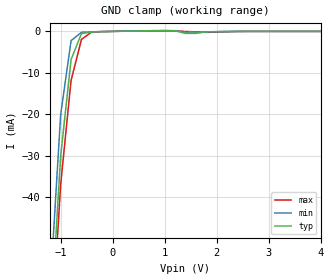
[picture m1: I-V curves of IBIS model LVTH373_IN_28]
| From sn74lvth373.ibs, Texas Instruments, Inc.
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|   Model LVTH373_IN_28
[Model]   LVTH373_IN_28
Model_type  Input
Polarity   Non-Inverting
Vinl = 0.8
Vinh = 2.0
| variable   typ   min   max
C_comp   3p   NA   NA
[Temperature Range]   40   -25   100
| Ambient temperature   25   -40   85
[Voltage range]   2.8   2.7   2.9
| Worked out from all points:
|   GND clamp passes 1 mA (typ) near -0.62 V on its own axis
[GND Clamp]
|   Voltage   I(typ)   I(min)   I(max)
-5V       -1.358A    -1.475A    -1.266A
-1.2V     -72.06mA   -61.52mA   -77.72mA
-1V       -29.98mA   -20.03mA   -36.89mA
-800mV    -6.803mA   -2.232mA   -11.84mA
-600mV    -520.1uA   -216.3uA   -1.92mA
-400mV    -101uA     -115.8uA   -121.8uA
-200mV    -48.7uA    -56.5uA    -43uA
1.2V      163.5uA    141.6uA    158.1uA
1.4V      -477.7uA   -297.5uA   -26.7uA
1.6V      -476.4uA   -217.6uA   -99.71uA
1.8V      -83.11uA   -130.5uA   -239.5uA
5V        198.3pA    92.82pA    3.595nA
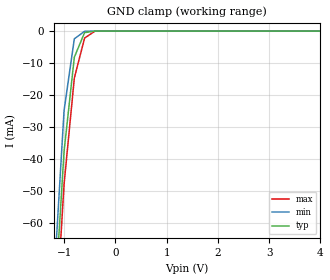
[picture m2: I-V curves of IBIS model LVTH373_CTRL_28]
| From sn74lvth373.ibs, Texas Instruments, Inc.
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|   Model LVTH373_CTRL_28
[Model]   LVTH373_CTRL_28
Model_type  Input
Polarity   Non-Inverting
Vinl = 0.8
Vinh = 2.0
| variable   typ   min   max
C_comp   3p   NA   NA
[Temperature Range]   40   -25   100
| Ambient temperature   25   -40   85
[Voltage range]   2.8   2.7   2.9
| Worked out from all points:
|   GND clamp passes 1 mA (typ) near -0.61 V on its own axis
[GND Clamp]
|   Voltage   I(typ)   I(min)   I(max)
-5V       -1.499A    -1.561A    -1.465A
-1.2V     -89.53mA   -78.73mA   -100.9mA
-1V       -37.49mA   -24.77mA   -47.75mA
-800mV    -8.144mA   -2.422mA   -14.66mA
-600mV    -479uA     -59.67uA   -2.181mA
-400mV    -1.318uA   -21.54nA   -41.73uA
5V        215.8pA    251.5pA    3.47nA
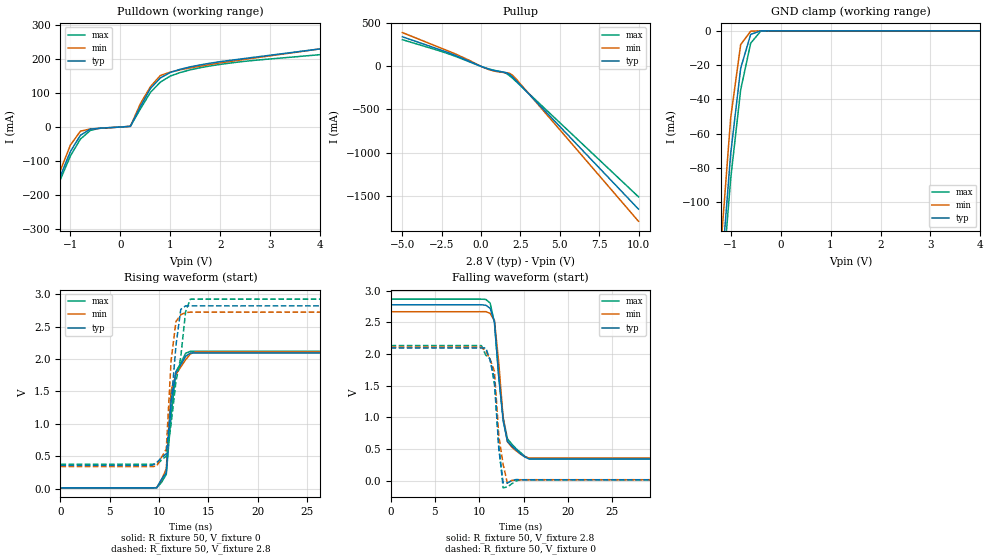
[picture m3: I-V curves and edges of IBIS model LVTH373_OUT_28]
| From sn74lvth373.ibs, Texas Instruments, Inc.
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|   Model LVTH373_OUT_28
[Model]   LVTH373_OUT_28
Model_type  3-state
Polarity   Inverting
Enable   Active-Low
Vmeas = 1.5v
Cref = 50pf
Rref = 500
Vref = 0V
| variable   typ   min   max
C_comp   7p   NA   NA
[Temperature Range]   40   -25   100
| Ambient temperature   25   -40   85
[Voltage range]   2.8   2.7   2.9
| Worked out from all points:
|   slope of the pulldown table from 0 to 0.42 V, typ, clamps not added: 6.46 ohm
|   slope of the pullup table from 0 to 0.42 V, typ, clamps not added: 15.3 ohm
|   GND clamp passes 1 mA (typ) near -0.50 V on its own axis
|   rising waveform, R_fixture 50, V_fixture 0: 20-80 % time 768ps typ, 785ps min, 787ps max; typ from 0.01 V to 2.09 V
|   falling waveform, R_fixture 50, V_fixture 2.8: 20-80 % time 1.03ns typ, 961ps min, 1.11ns max; typ from 2.78 V to 0.34 V
|   rising waveform, R_fixture 50, V_fixture 2.8: 20-80 % time 885ps typ, 636ps min, 1.36ns max; typ from 0.357 V to 2.82 V
|   falling waveform, R_fixture 50, V_fixture 0: 20-80 % time 672ps typ, 770ps min, 803ps max; typ from 2.1 V to 0.012 V
[Pulldown]
|   Voltage   I(typ)   I(min)   I(max)
-5V       -1.735A    -1.814A    -1.694A
-1.6V     -310.8mA   -304.6mA   -315.7mA
-1V       -71.87mA   -52.82mA   -84.79mA
-800mV    -24.38mA   -12.48mA   -35.5mA
-600mV    -6.293mA   -5.811mA   -10.16mA
200mV     1.733mA    1.692mA    1.86mA
600mV     112.6mA    117.8mA    101.1mA
800mV     143.7mA    150.8mA    131.4mA
1.2V      169.1mA    167.5mA    159.6mA
2.4V      199.1mA    196.2mA    190.9mA
7V        284.6mA    290.1mA    249.7mA
10V       340.4mA    351.3mA    287.5mA
[Pullup]
|   Voltage   I(typ)   I(min)   I(max)
-5V       343.4mA    392.2mA    309.6mA
-2.4V     180mA      201.8mA    165.9mA
400mV     -26.42mA   -30.93mA   -24.54mA
1.4V      -66.01mA   -70.06mA   -66.23mA
1.8V      -92.52mA   -80.02mA   -106.8mA
2V        -123.2mA   -103.6mA   -137.7mA
10V       -1.656A    -1.797A    -1.513A
[GND Clamp]
|   Voltage   I(typ)   I(min)   I(max)
-5V       -1.644A    -1.71A     -1.602A
-1.2V     -145.8mA   -127.4mA   -157.9mA
-1V       -71.56mA   -50.65mA   -86.13mA
-800mV    -21.81mA   -7.986mA   -34.35mA
-600mV    -2.085mA   -211.9uA   -7.209mA
-400mV    -7.958uA   -21.98nA   -237.9uA
5V        55.18nA    132.9nA    97.59nA
[Ramp]
| variable   typ   min   max
dV/dt_r  1.230E+00/4.620E-10  1.188E+00/4.190E-10  1.278E+00/4.810E-10
dV/dt_f  1.440E+00/6.870E-10  1.380E+00/6.150E-10  1.488E+00/7.190E-10
R_load = 50
[Rising Waveform]
R_fixture = 50
V_fixture = 0
V_fixture_min = 0
V_fixture_max = 0
C_fixture = 0pf
L_fixture = 0nH
|   Time   V(typ)   V(min)   V(max)
0s        10.06mV    10.66mV    10.15mV
9.766ns   10.07mV    12.89mV    10.85mV
10.25ns   138.9mV    131.9mV    93.08mV
10.74ns   244.7mV    304.9mV    219.4mV
11.23ns   1.345V     1.518V     1.118V
11.72ns   1.798V     1.762V     1.807V
12.7ns    2.044V     1.99V      2.09V
13.18ns   2.094V     2.08V      2.12V
13.67ns   2.094V     2.11V      2.12V
49.71ns   2.094V     2.11V      2.12V
[Falling Waveform]
R_fixture = 50
V_fixture = 2.8
V_fixture_min = 2.7
V_fixture_max = 2.9
C_fixture = 0pf
L_fixture = 0nH
|   Time   V(typ)   V(min)   V(max)
0s        2.777V     2.667V     2.866V
10.25ns   2.777V     2.667V     2.866V
11.23ns   2.722V     2.64V      2.805V
11.72ns   2.509V     2.527V     2.489V
12.21ns   1.638V     1.85V      1.628V
12.7ns    943mV      982.2mV    993.1mV
13.18ns   620.4mV    613.7mV    661.5mV
14.16ns   485.4mV    468.8mV    502.8mV
15.63ns   340.1mV    355.1mV    347.8mV
49.71ns   340.1mV    355.1mV    347.8mV
[Rising Waveform]
R_fixture = 50
V_fixture = 2.8
V_fixture_min = 2.7
V_fixture_max = 2.9
C_fixture = 0pf
L_fixture = 0nH
|   Time   V(typ)   V(min)   V(max)
0s        357mV      339.9mV    375.5mV
9.277ns   357mV      338.8mV    375.5mV
9.766ns   401.4mV    344.5mV    370.4mV
10.74ns   537.6mV    608.4mV    500.8mV
11.23ns   1.297V     1.977V     998.1mV
11.72ns   2.208V     2.581V     1.65V
12.21ns   2.768V     2.685V     2.03V
12.7ns    2.823V     2.719V     2.733V
13.18ns   2.823V     2.726V     2.927V
49.71ns   2.823V     2.726V     2.927V
[Falling Waveform]
R_fixture = 50
V_fixture = 0
V_fixture_min = 0
V_fixture_max = 0
C_fixture = 0pf
L_fixture = 0nH
|   Time   V(typ)   V(min)   V(max)
0s        2.095V     2.108V     2.132V
10.25ns   2.095V     2.108V     2.132V
10.74ns   2.095V     2.046V     1.98V
11.23ns   1.902V     1.912V     1.921V
11.72ns   1.606V     1.724V     1.521V
12.21ns   495.5mV    707.1mV    550.5mV
12.7ns    -36.58mV   252.8mV    -115.7mV
13.18ns   -38.42mV   -42.8mV    -101mV
14.65ns   11.73mV    12.68mV    12.57mV
49.71ns   11.73mV    12.67mV    12.57mV
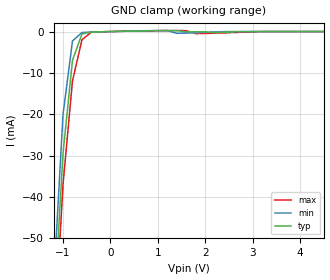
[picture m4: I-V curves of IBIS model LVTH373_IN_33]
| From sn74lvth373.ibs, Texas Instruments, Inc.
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|   Model LVTH373_IN_33
[Model]   LVTH373_IN_33
Model_type  Input
Polarity   Non-Inverting
Vinl = 0.8V
Vinh = 2.0V
| variable   typ   min   max
C_comp   3p   NA   NA
[Temperature Range]   40   -25   100
| Ambient temperature   25   -40   85
[Voltage range]   3.3   3.0   3.6
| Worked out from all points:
|   GND clamp passes 1 mA (typ) near -0.61 V on its own axis
[GND Clamp]
|   Voltage   I(typ)   I(min)   I(max)
-5V       -1.261A    -1.353A    -1.203A
-1.2V     -69.48mA   -61.6mA    -77.82mA
-1V       -29.48mA   -20.11mA   -37.03mA
-800mV    -6.923mA   -2.26mA    -11.95mA
-600mV    -562.6uA   -228.5uA   -1.969mA
-400mV    -112.8uA   -125uA     -137.3uA
-200mV    -54.88uA   -61.33uA   -50.28uA
1.2V      242.3uA    248.8uA    233.4uA
1.4V      234.1uA    -426.3uA   244.2uA
1.6V      -63.27uA   -361.3uA   226.5uA
1.8V      -49.28uA   -275.9uA   -507.5uA
5V        33.82pA    -60pA      4.033nA
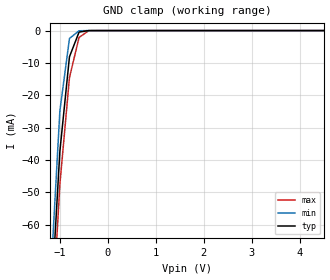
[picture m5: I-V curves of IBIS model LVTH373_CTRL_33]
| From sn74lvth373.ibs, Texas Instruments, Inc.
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|   Model LVTH373_CTRL_33
[Model]   LVTH373_CTRL_33
Model_type  Input
Polarity   Non-Inverting
Vinl = 0.8V
Vinh = 2.0V
| variable   typ   min   max
C_comp   3p   NA   NA
[Temperature Range]   40   -25   100
| Ambient temperature   25   -40   85
[Voltage range]   3.3   3.0   3.6
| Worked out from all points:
|   GND clamp passes 1 mA (typ) near -0.61 V on its own axis
[GND Clamp]
|   Voltage   I(typ)   I(min)   I(max)
-5V       -1.507A    -1.562A    -1.421A
-1.2V     -89.21mA   -78.87mA   -100.1mA
-1V       -37.32mA   -24.85mA   -47.57mA
-800mV    -8.093mA   -2.447mA   -14.52mA
-600mV    -471.3uA   -60.21uA   -2.13mA
-400mV    -1.284uA   -21.84nA   -38.81uA
5V        250.9pA    693.9pA    3.447nA
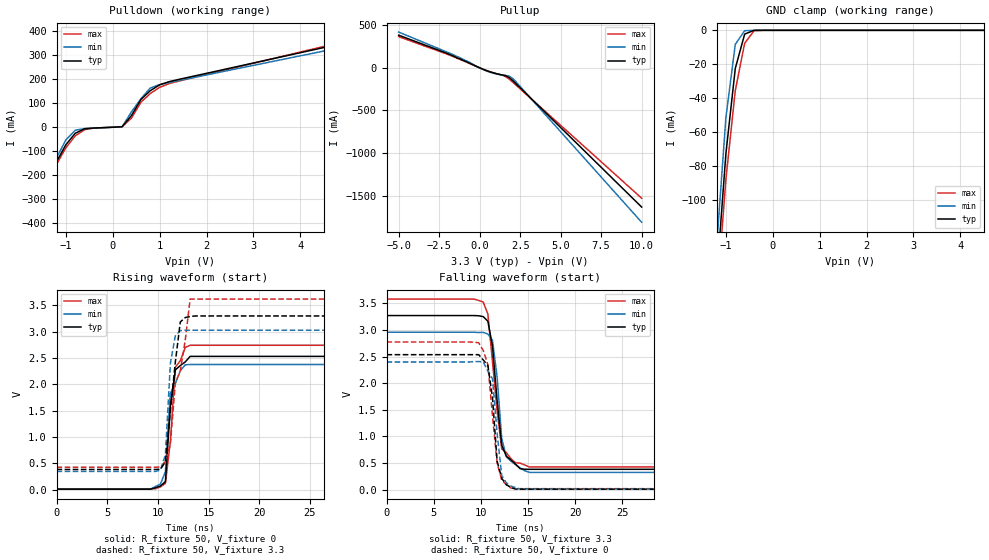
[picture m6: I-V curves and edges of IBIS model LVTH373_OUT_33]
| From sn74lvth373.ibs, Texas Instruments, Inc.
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|   Model LVTH373_OUT_33
[Model]   LVTH373_OUT_33
Model_type  3-state
Polarity   Inverting
Enable   Active-Low
Vmeas = 1.5V
Cref = 50pf
Rref = 500
Vref = 0V
| variable   typ   min   max
C_comp   7p   NA   NA
[Temperature Range]   40   -25   100
| Ambient temperature   25   -40   85
[Voltage range]   3.3   3.0   3.6
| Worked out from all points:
|   slope of the pulldown table from 0 to 0.495 V, typ, clamps not added: 6.12 ohm
|   slope of the pullup table from 0 to 0.495 V, typ, clamps not added: 13.2 ohm
|   GND clamp passes 1 mA (typ) near -0.49 V on its own axis
|   rising waveform, R_fixture 50, V_fixture 0: 20-80 % time 682ps typ, 632ps min, 662ps max; typ from 0.013 V to 2.53 V
|   falling waveform, R_fixture 50, V_fixture 3.3: 20-80 % time 906ps typ, 867ps min, 1.08ns max; typ from 3.27 V to 0.384 V
|   rising waveform, R_fixture 50, V_fixture 3.3: 20-80 % time 946ps typ, 513ps min, 1.47ns max; typ from 0.386 V to 3.3 V
|   falling waveform, R_fixture 50, V_fixture 0: 20-80 % time 765ps typ, 763ps min, 876ps max; typ from 2.54 V to 0.01 V
[Pulldown]
|   Voltage   I(typ)   I(min)   I(max)
-5V       -1.731A    -1.815A    -1.697A
-2V       -478.4mA   -482.8mA   -479.4mA
-1.8V     -394.9mA   -394mA     -398.2mA
-1.2V     -144.4mA   -127.6mA   -154.7mA
-800mV    -25.43mA   -12.78mA   -36.35mA
-600mV    -6.664mA   -5.956mA   -10.65mA
200mV     1.724mA    1.679mA    1.874mA
800mV     152.2mA    163.2mA    140.2mA
1.2V      189.6mA    186.1mA    181.6mA
6.2V      405.2mA    385.1mA    416.3mA
7.2V      448.2mA    424.9mA    463.1mA
10V       568.6mA    536.3mA    594.2mA
[Pullup]
|   Voltage   I(typ)   I(min)   I(max)
-5V       383.8mA    420mA      366.5mA
-1.6V     137.3mA    151.4mA    129.4mA
400mV     -30.82mA   -34.61mA   -29.72mA
1.4V      -83.86mA   -84.18mA   -86.1mA
1.8V      -111.2mA   -95.59mA   -129mA
2V        -141.3mA   -118.2mA   -161.2mA
10V       -1.635A    -1.813A    -1.531A
[GND Clamp]
|   Voltage   I(typ)   I(min)   I(max)
-5V       -1.65A     -1.715A    -1.615A
-1.2V     -147.1mA   -128.2mA   -160mA
-1V       -72.59mA   -51.29mA   -87.71mA
-800mV    -22.48mA   -8.248mA   -35.41mA
-600mV    -2.233mA   -220.9uA   -7.623mA
-400mV    -8.73uA    -21.64nA   -264.5uA
5V        57.51nA    120.8nA    97.88nA
[Ramp]
| variable   typ   min   max
dV/dt_r  1.512E+00/3.930E-10  1.392E+00/3.830E-10  1.668E+00/4.090E-10
dV/dt_f  1.704E+00/6.210E-10  1.542E+00/5.110E-10  1.860E+00/5.790E-10
R_load = 50
[Rising Waveform]
R_fixture = 50
V_fixture = 0
V_fixture_min = 0
V_fixture_max = 0
C_fixture = 0pf
L_fixture = 0nH
|   Time   V(typ)   V(min)   V(max)
0s        12.64mV    13.94mV    20.38mV
9.277ns   12.64mV    13.94mV    20.38mV
10.25ns   71.66mV    108mV      55.58mV
10.74ns   158.2mV    344.5mV    122.8mV
11.23ns   1.583V     1.834V     917.5mV
11.72ns   2.276V     2.021V     2.33V
12.21ns   2.359V     2.26V      2.449V
12.7ns    2.428V     2.374V     2.704V
13.18ns   2.533V     2.379V     2.744V
49.71ns   2.533V     2.379V     2.744V
[Falling Waveform]
R_fixture = 50
V_fixture = 3.3
V_fixture_min = 3
V_fixture_max = 3.6
C_fixture = 0pf
L_fixture = 0nH
|   Time   V(typ)   V(min)   V(max)
0s        3.272V     2.959V     3.582V
10.25ns   3.252V     2.956V     3.525V
10.74ns   3.166V     2.925V     3.303V
11.23ns   2.696V     2.808V     2.403V
11.72ns   1.674V     2.115V     1.478V
12.21ns   837.1mV    957.4mV    766.5mV
12.7ns    627.9mV    620.3mV    696.3mV
13.67ns   480.2mV    470.7mV    504.9mV
15.14ns   383.6mV    325.6mV    428.1mV
49.71ns   383.6mV    325.6mV    428.1mV
[Rising Waveform]
R_fixture = 50
V_fixture = 3.3
V_fixture_min = 3
V_fixture_max = 3.6
C_fixture = 0pf
L_fixture = 0nH
|   Time   V(typ)   V(min)   V(max)
0s        386.3mV    349.2mV    427.7mV
9.766ns   386.3mV    349.2mV    427.7mV
10.25ns   391.8mV    375.5mV    434.8mV
10.74ns   529.8mV    662.7mV    539.9mV
11.23ns   1.498V     2.403V     877.9mV
11.72ns   2.425V     2.924V     2.027V
12.21ns   3.186V     3.022V     2.259V
12.7ns    3.27V      3.03V      2.845V
13.18ns   3.289V     3.03V      3.621V
49.71ns   3.3V       3.03V      3.621V
[Falling Waveform]
R_fixture = 50
V_fixture = 0
V_fixture_min = 0
V_fixture_max = 0
C_fixture = 0pf
L_fixture = 0nH
|   Time   V(typ)   V(min)   V(max)
0s        2.537V     2.4V       2.775V
9.766ns   2.537V     2.407V     2.762V
10.25ns   2.438V     2.403V     2.617V
10.74ns   2.336V     2.225V     2.351V
11.23ns   1.726V     2.086V     1.389V
11.72ns   534.5mV    1.062V     500mV
12.21ns   214.7mV    265.5mV    178.6mV
13.18ns   45.46mV    69.1mV     31.28mV
14.16ns   10.14mV    13.09mV    19.79mV
49.71ns   10.14mV    13.09mV    19.79mV
